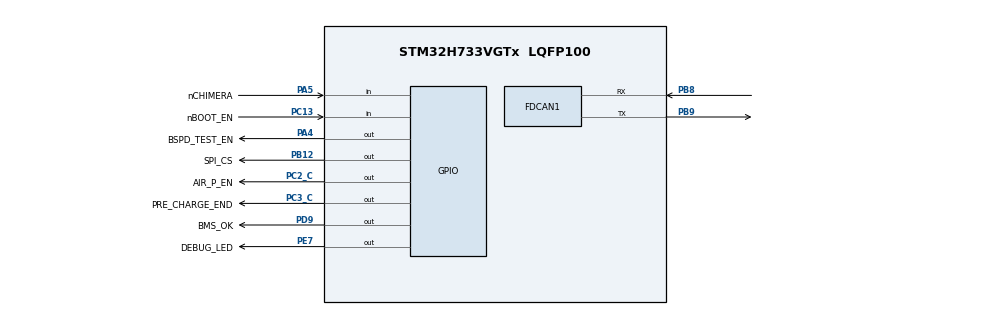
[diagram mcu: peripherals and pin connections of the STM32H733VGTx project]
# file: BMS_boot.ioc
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CORTEX_M7.CPU_DCache=Disabled
CORTEX_M7.CPU_ICache=Disabled
CRC.InputDataFormat=CRC_INPUTDATA_FORMAT_WORDS
FDCAN1.AutoRetransmission=ENABLE
FDCAN1.CalculateBaudRateNominal=941176
FDCAN1.CalculateTimeBitNominal=1062
FDCAN1.CalculateTimeQuantumNominal=62.5
FDCAN1.NominalPrescaler=6
FDCAN1.NominalSyncJumpWidth=3
FDCAN1.NominalTimeSeg1=13
FDCAN1.NominalTimeSeg2=3
FDCAN1.RxFifo0ElmtsNbr=1
FDCAN1.RxFifo1ElmtsNbr=0
FDCAN1.StdFiltersNbr=1
FDCAN1.TxFifoQueueElmtsNbr=1
FREERTOS.Tasks01=interfaceTask,32,512,runInterfaceTask,Default,NULL,Static,interfaceTaskBuffer,interfaceTaskControlBlock;tickTask,24,512,runTickTask,Default,NULL,Static,tickTaskBuffer,tickTaskControlBlock;canTxTask,16,512,runCanTxTask,Default,NULL,Static,canTxTaskBuffer,canTxTaskControlBlock
FREERTOS.configUSE_NEWLIB_REENTRANT=1
Mcu.Family=STM32H7
Mcu.Name=STM32H733VGTx
Mcu.Package=LQFP100
NVIC.FDCAN1_IT0_IRQn=true\:5\:0\:false\:false\:true\:true\:true\:true\:true
NVIC.FDCAN1_IT1_IRQn=true\:5\:0\:false\:false\:true\:true\:true\:true\:true
NVIC.PriorityGroup=NVIC_PRIORITYGROUP_4
NVIC.TIM6_DAC_IRQn=true\:15\:0\:false\:false\:true\:false\:false\:true\:true
NVIC.TimeBase=TIM6_DAC_IRQn
NVIC.TimeBaseIP=TIM6
PA4.GPIO_Label=BSPD_TEST_EN
PA4.GPIO_PuPd=GPIO_NOPULL
PA4.Signal=GPIO_Output
PA5.GPIO_Label=nCHIMERA
PA5.GPIO_PuPd=GPIO_PULLUP
PA5.Signal=GPIO_Input
PB12.GPIO_Label=SPI_CS
PB12.GPIO_PuPd=GPIO_PULLDOWN
PB12.Signal=GPIO_Output
PB8.Mode=FDCAN_Activate
PB8.Signal=FDCAN1_RX
PB9.Mode=FDCAN_Activate
PB9.Signal=FDCAN1_TX
PC13.GPIO_Label=nBOOT_EN
PC13.GPIO_PuPd=GPIO_PULLUP
PC13.Signal=GPIO_Input
PC2_C.GPIO_Label=AIR_P_EN
PC2_C.GPIO_PuPd=GPIO_NOPULL
PC2_C.PinState=GPIO_PIN_RESET
PC2_C.Signal=GPIO_Output
PC3_C.GPIO_Label=PRE_CHARGE_END
PC3_C.GPIO_PuPd=GPIO_NOPULL
PC3_C.GPIO_Speed=GPIO_SPEED_FREQ_LOW
PC3_C.Signal=GPIO_Output
PD9.GPIO_Label=BMS_OK
PD9.GPIO_PuPd=GPIO_NOPULL
PD9.PinState=GPIO_PIN_SET
PD9.Signal=GPIO_Output
PE7.GPIO_Label=DEBUG_LED
PE7.GPIO_PuPd=GPIO_NOPULL
PE7.Signal=GPIO_Output
PH0-OSC_IN.Mode=HSE-External-Oscillator
PH0-OSC_IN.Signal=RCC_OSC_IN
PH1-OSC_OUT.Mode=HSE-External-Oscillator
PH1-OSC_OUT.Signal=RCC_OSC_OUT
ProjectManager.HeapSize=0x00
ProjectManager.StackSize=0x400
ProjectManager.TargetToolchain=STM32CubeIDE
RCC.ADCFreq_Value=96000000
RCC.APB1Freq_Value=128000000
RCC.APB2Freq_Value=128000000
RCC.APB3Freq_Value=128000000
RCC.APB4Freq_Value=128000000
RCC.CortexFreq_Value=512000000
RCC.D1PPRE=RCC_APB3_DIV2
RCC.D2PPRE1=RCC_APB1_DIV2
RCC.D2PPRE2=RCC_APB2_DIV2
RCC.D3PPRE=RCC_APB4_DIV2
RCC.DIVM1=1
RCC.DIVM2=1
RCC.DIVN1=64
RCC.DIVN2=24
RCC.DIVP1=1
RCC.DIVQ1=4
RCC.FDCANCLockSelection=RCC_FDCANCLKSOURCE_PLL2
RCC.HCLKFreq_Value=256000000
RCC.HPRE=RCC_HCLK_DIV2
RCC.HSE_VALUE=8000000
RCC.PLL2FRACN=0
RCC.PLL3FRACN=0
RCC.PLLFRACN=0
RCC.PLLSourceVirtual=RCC_PLLSOURCE_HSE
RCC.SYSCLKFreq_VALUE=512000000
RCC.SYSCLKSource=RCC_SYSCLKSOURCE_PLLCLK
RCC.USBFreq_Value=128000000
VP_CRC_VS_CRC.Mode=CRC_Activate
VP_FREERTOS_VS_CMSIS_V2.Mode=CMSIS_V2
VP_SYS_VS_tim6.Mode=TIM6
board=custom

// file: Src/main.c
/* USER CODE BEGIN Header */
/**
 ******************************************************************************
 * @file           : main.c
 * @brief          : Main program body
 ******************************************************************************
 * @attention
 *
 * Copyright (c) 2023 STMicroelectronics.
 * All rights reserved.
 *
 * This software is licensed under terms that can be found in the LICENSE file
 * in the root directory of this software component.
 * If no LICENSE file comes with this software, it is provided AS-IS.
 *
 ******************************************************************************
 */
/* USER CODE END Header */
#include "main.h"
#include "cmsis_os.h"

/* USER CODE BEGIN Includes */
#include "bootloader.h"
#include "hw_fdcan.h"
#include "hw_utils.h"
#include "hw_error.h"
#include "io_canQueue.h"
#include <assert.h>
/* USER CODE END Includes */

typedef StaticTask_t osStaticThreadDef_t;

CRC_HandleTypeDef hcrc;

FDCAN_HandleTypeDef hfdcan1;

/* Definitions for interfaceTask */
osThreadId_t         interfaceTaskHandle;
uint32_t             interfaceTaskBuffer[512];
osStaticThreadDef_t  interfaceTaskControlBlock;
const osThreadAttr_t interfaceTask_attributes = {
    .name       = "interfaceTask",
    .cb_mem     = &interfaceTaskControlBlock,
    .cb_size    = sizeof(interfaceTaskControlBlock),
    .stack_mem  = &interfaceTaskBuffer[0],
    .stack_size = sizeof(interfaceTaskBuffer),
    .priority   = (osPriority_t)osPriorityAboveNormal,
};
/* Definitions for tickTask */
osThreadId_t         tickTaskHandle;
uint32_t             tickTaskBuffer[512];
osStaticThreadDef_t  tickTaskControlBlock;
const osThreadAttr_t tickTask_attributes = {
    .name       = "tickTask",
    .cb_mem     = &tickTaskControlBlock,
    .cb_size    = sizeof(tickTaskControlBlock),
    .stack_mem  = &tickTaskBuffer[0],
    .stack_size = sizeof(tickTaskBuffer),
    .priority   = (osPriority_t)osPriorityNormal,
};
/* Definitions for canTxTask */
osThreadId_t         canTxTaskHandle;
uint32_t             canTxTaskBuffer[512];
osStaticThreadDef_t  canTxTaskControlBlock;
const osThreadAttr_t canTxTask_attributes = {
    .name       = "canTxTask",
    .cb_mem     = &canTxTaskControlBlock,
    .cb_size    = sizeof(canTxTaskControlBlock),
    .stack_mem  = &canTxTaskBuffer[0],
    .stack_size = sizeof(canTxTaskBuffer),
    .priority   = (osPriority_t)osPriorityBelowNormal,
};

void        SystemClock_Config(void);
static void MX_GPIO_Init(void);
static void MX_CRC_Init(void);
static void MX_FDCAN1_Init(void);
void        runInterfaceTask(void *argument);
void        runTickTask(void *argument);
void        runCanTxTask(void *argument);

/* USER CODE BEGIN 0 */
CanHandle can = { .hcan = &hfdcan1, .bus_num = 1, .receive_callback = io_canQueue_pushRx };
/* USER CODE END 0 */

int main(void)
{
    /* USER CODE BEGIN 1 */
    bootloader_preInit();
    /* USER CODE END 1 */

    /* MCU Configuration--------------------------------------------------------*/

    /* Reset of all peripherals, Initializes the Flash interface and the Systick. */
    HAL_Init();

    /* Configure the system clock */
    SystemClock_Config();

    /* Initialize all configured peripherals */
    MX_GPIO_Init();
    MX_CRC_Init();
    MX_FDCAN1_Init();
    /* USER CODE BEGIN 2 */
    bootloader_init();
    /* USER CODE END 2 */

    /* Init scheduler */
    osKernelInitialize();

    /* Create the thread(s) */
    /* creation of interfaceTask */
    interfaceTaskHandle = osThreadNew(runInterfaceTask, NULL, &interfaceTask_attributes);

    /* creation of tickTask */
    tickTaskHandle = osThreadNew(runTickTask, NULL, &tickTask_attributes);

    /* creation of canTxTask */
    canTxTaskHandle = osThreadNew(runCanTxTask, NULL, &canTxTask_attributes);

    /* Start scheduler */
    osKernelStart();

    /* We should never get here as control is now taken by the scheduler */
    /* Infinite loop */
    while (1)
    {

    }
}

void SystemClock_Config(void)
{
    RCC_OscInitTypeDef RCC_OscInitStruct = { 0 };
    RCC_ClkInitTypeDef RCC_ClkInitStruct = { 0 };

    /** Supply configuration update enable
     */
    HAL_PWREx_ConfigSupply(PWR_LDO_SUPPLY);

    /** Configure the main internal regulator output voltage
     */
    __HAL_PWR_VOLTAGESCALING_CONFIG(PWR_REGULATOR_VOLTAGE_SCALE3);

    while (!__HAL_PWR_GET_FLAG(PWR_FLAG_VOSRDY))
    {
    }

    /** Initializes the RCC Oscillators according to the specified parameters
     * in the RCC_OscInitTypeDef structure.
     */
    RCC_OscInitStruct.OscillatorType = RCC_OSCILLATORTYPE_HSE;
    RCC_OscInitStruct.HSEState       = RCC_HSE_ON;
    RCC_OscInitStruct.PLL.PLLState   = RCC_PLL_ON;
    RCC_OscInitStruct.PLL.PLLSource  = RCC_PLLSOURCE_HSE;
    RCC_OscInitStruct.PLL.PLLM       = 1;
    RCC_OscInitStruct.PLL.PLLN       = 24;
    RCC_OscInitStruct.PLL.PLLP       = 1;
    RCC_OscInitStruct.PLL.PLLQ       = 4;
    RCC_OscInitStruct.PLL.PLLR       = 2;
    RCC_OscInitStruct.PLL.PLLRGE     = RCC_PLL1VCIRANGE_3;
    RCC_OscInitStruct.PLL.PLLVCOSEL  = RCC_PLL1VCOWIDE;
    RCC_OscInitStruct.PLL.PLLFRACN   = 0;
    if (HAL_RCC_OscConfig(&RCC_OscInitStruct) != HAL_OK)
    {
        Error_Handler();
    }

    /** Initializes the CPU, AHB and APB buses clocks
     */
    RCC_ClkInitStruct.ClockType = RCC_CLOCKTYPE_HCLK | RCC_CLOCKTYPE_SYSCLK | RCC_CLOCKTYPE_PCLK1 |
                                  RCC_CLOCKTYPE_PCLK2 | RCC_CLOCKTYPE_D3PCLK1 | RCC_CLOCKTYPE_D1PCLK1;
    RCC_ClkInitStruct.SYSCLKSource   = RCC_SYSCLKSOURCE_PLLCLK;
    RCC_ClkInitStruct.SYSCLKDivider  = RCC_SYSCLK_DIV2;
    RCC_ClkInitStruct.AHBCLKDivider  = RCC_HCLK_DIV2;
    RCC_ClkInitStruct.APB3CLKDivider = RCC_APB3_DIV2;
    RCC_ClkInitStruct.APB1CLKDivider = RCC_APB1_DIV2;
    RCC_ClkInitStruct.APB2CLKDivider = RCC_APB2_DIV2;
    RCC_ClkInitStruct.APB4CLKDivider = RCC_APB4_DIV2;

    if (HAL_RCC_ClockConfig(&RCC_ClkInitStruct, FLASH_LATENCY_1) != HAL_OK)
    {
        Error_Handler();
    }
}

static void MX_CRC_Init(void)
{

    hcrc.Instance                     = CRC;
    hcrc.Init.DefaultPolynomialUse    = DEFAULT_POLYNOMIAL_ENABLE;
    hcrc.Init.DefaultInitValueUse     = DEFAULT_INIT_VALUE_ENABLE;
    hcrc.Init.InputDataInversionMode  = CRC_INPUTDATA_INVERSION_NONE;
    hcrc.Init.OutputDataInversionMode = CRC_OUTPUTDATA_INVERSION_DISABLE;
    hcrc.InputDataFormat              = CRC_INPUTDATA_FORMAT_WORDS;
    if (HAL_CRC_Init(&hcrc) != HAL_OK)
    {
        Error_Handler();
    }
}

static void MX_FDCAN1_Init(void)
{

    hfdcan1.Instance                  = FDCAN1;
    hfdcan1.Init.FrameFormat          = FDCAN_FRAME_CLASSIC;
    hfdcan1.Init.Mode                 = FDCAN_MODE_NORMAL;
    hfdcan1.Init.AutoRetransmission   = ENABLE;
    hfdcan1.Init.TransmitPause        = DISABLE;
    hfdcan1.Init.ProtocolException    = DISABLE;
    hfdcan1.Init.NominalPrescaler     = 6;
    hfdcan1.Init.NominalSyncJumpWidth = 4;
    hfdcan1.Init.NominalTimeSeg1      = 13;
    hfdcan1.Init.NominalTimeSeg2      = 2;
    hfdcan1.Init.DataPrescaler        = 1;
    hfdcan1.Init.DataSyncJumpWidth    = 1;
    hfdcan1.Init.DataTimeSeg1         = 1;
    hfdcan1.Init.DataTimeSeg2         = 1;
    hfdcan1.Init.MessageRAMOffset     = 0;
    hfdcan1.Init.StdFiltersNbr        = 1;
    hfdcan1.Init.ExtFiltersNbr        = 0;
    hfdcan1.Init.RxFifo0ElmtsNbr      = 1;
    hfdcan1.Init.RxFifo0ElmtSize      = FDCAN_DATA_BYTES_8;
    hfdcan1.Init.RxFifo1ElmtsNbr      = 0;
    hfdcan1.Init.RxFifo1ElmtSize      = FDCAN_DATA_BYTES_8;
    hfdcan1.Init.RxBuffersNbr         = 0;
    hfdcan1.Init.RxBufferSize         = FDCAN_DATA_BYTES_8;
    hfdcan1.Init.TxEventsNbr          = 0;
    hfdcan1.Init.TxBuffersNbr         = 0;
    hfdcan1.Init.TxFifoQueueElmtsNbr  = 1;
    hfdcan1.Init.TxFifoQueueMode      = FDCAN_TX_FIFO_OPERATION;
    hfdcan1.Init.TxElmtSize           = FDCAN_DATA_BYTES_8;
    if (HAL_FDCAN_Init(&hfdcan1) != HAL_OK)
    {
        Error_Handler();
    }
}

static void MX_GPIO_Init(void)
{
    GPIO_InitTypeDef GPIO_InitStruct = { 0 };

    /* GPIO Ports Clock Enable */
    __HAL_RCC_GPIOC_CLK_ENABLE();
    __HAL_RCC_GPIOH_CLK_ENABLE();
    __HAL_RCC_GPIOA_CLK_ENABLE();
    __HAL_RCC_GPIOE_CLK_ENABLE();
    __HAL_RCC_GPIOB_CLK_ENABLE();
    __HAL_RCC_GPIOD_CLK_ENABLE();

    /*Configure GPIO pin Output Level */
    HAL_GPIO_WritePin(GPIOC, AIR_P_EN_Pin | PRE_CHARGE_END_Pin, GPIO_PIN_RESET);

    /*Configure GPIO pin Output Level */
    HAL_GPIO_WritePin(BSPD_TEST_EN_GPIO_Port, BSPD_TEST_EN_Pin, GPIO_PIN_RESET);

    /*Configure GPIO pin Output Level */
    HAL_GPIO_WritePin(DEBUG_LED_GPIO_Port, DEBUG_LED_Pin, GPIO_PIN_RESET);

    /*Configure GPIO pin Output Level */
    HAL_GPIO_WritePin(SPI_CS_GPIO_Port, SPI_CS_Pin, GPIO_PIN_RESET);

    /*Configure GPIO pin Output Level */
    HAL_GPIO_WritePin(BMS_OK_GPIO_Port, BMS_OK_Pin, GPIO_PIN_SET);

    /*Configure GPIO pin : nBOOT_EN_Pin */
    GPIO_InitStruct.Pin  = nBOOT_EN_Pin;
    GPIO_InitStruct.Mode = GPIO_MODE_INPUT;
    GPIO_InitStruct.Pull = GPIO_PULLUP;
    HAL_GPIO_Init(nBOOT_EN_GPIO_Port, &GPIO_InitStruct);

    /*Configure GPIO pins : AIR_P_EN_Pin PRE_CHARGE_END_Pin */
    GPIO_InitStruct.Pin   = AIR_P_EN_Pin | PRE_CHARGE_END_Pin;
    GPIO_InitStruct.Mode  = GPIO_MODE_OUTPUT_PP;
    GPIO_InitStruct.Pull  = GPIO_NOPULL;
    GPIO_InitStruct.Speed = GPIO_SPEED_FREQ_LOW;
    HAL_GPIO_Init(GPIOC, &GPIO_InitStruct);

    /*Configure GPIO pin : BSPD_TEST_EN_Pin */
    GPIO_InitStruct.Pin   = BSPD_TEST_EN_Pin;
    GPIO_InitStruct.Mode  = GPIO_MODE_OUTPUT_PP;
    GPIO_InitStruct.Pull  = GPIO_NOPULL;
    GPIO_InitStruct.Speed = GPIO_SPEED_FREQ_LOW;
    HAL_GPIO_Init(BSPD_TEST_EN_GPIO_Port, &GPIO_InitStruct);

    /*Configure GPIO pin : nCHIMERA_Pin */
    GPIO_InitStruct.Pin  = nCHIMERA_Pin;
    GPIO_InitStruct.Mode = GPIO_MODE_INPUT;
    GPIO_InitStruct.Pull = GPIO_PULLUP;
    HAL_GPIO_Init(nCHIMERA_GPIO_Port, &GPIO_InitStruct);

    /*Configure GPIO pin : DEBUG_LED_Pin */
    GPIO_InitStruct.Pin   = DEBUG_LED_Pin;
    GPIO_InitStruct.Mode  = GPIO_MODE_OUTPUT_PP;
    GPIO_InitStruct.Pull  = GPIO_NOPULL;
    GPIO_InitStruct.Speed = GPIO_SPEED_FREQ_LOW;
    HAL_GPIO_Init(DEBUG_LED_GPIO_Port, &GPIO_InitStruct);

    /*Configure GPIO pin : SPI_CS_Pin */
    GPIO_InitStruct.Pin   = SPI_CS_Pin;
    GPIO_InitStruct.Mode  = GPIO_MODE_OUTPUT_PP;
    GPIO_InitStruct.Pull  = GPIO_PULLDOWN;
    GPIO_InitStruct.Speed = GPIO_SPEED_FREQ_LOW;
    HAL_GPIO_Init(SPI_CS_GPIO_Port, &GPIO_InitStruct);

    /*Configure GPIO pin : BMS_OK_Pin */
    GPIO_InitStruct.Pin   = BMS_OK_Pin;
    GPIO_InitStruct.Mode  = GPIO_MODE_OUTPUT_PP;
    GPIO_InitStruct.Pull  = GPIO_NOPULL;
    GPIO_InitStruct.Speed = GPIO_SPEED_FREQ_LOW;
    HAL_GPIO_Init(BMS_OK_GPIO_Port, &GPIO_InitStruct);

}

void runInterfaceTask(void *argument)
{
    /* USER CODE BEGIN 5 */
    bootloader_runInterfaceTask();
    /* USER CODE END 5 */
}

void runTickTask(void *argument)
{
    /* USER CODE BEGIN runTickTask */
    bootloader_runTickTask();
    /* USER CODE END runTickTask */
}

void runCanTxTask(void *argument)
{
    /* USER CODE BEGIN runCanTxTask */
    bootloader_runCanTxTask();
    /* USER CODE END runCanTxTask */
}

void HAL_TIM_PeriodElapsedCallback(TIM_HandleTypeDef *htim)
{
    if (htim->Instance == TIM6)
    {
        HAL_IncTick();
    }
}

void Error_Handler(void)
{
    __disable_irq();
    while (1)
    {
    }
}
